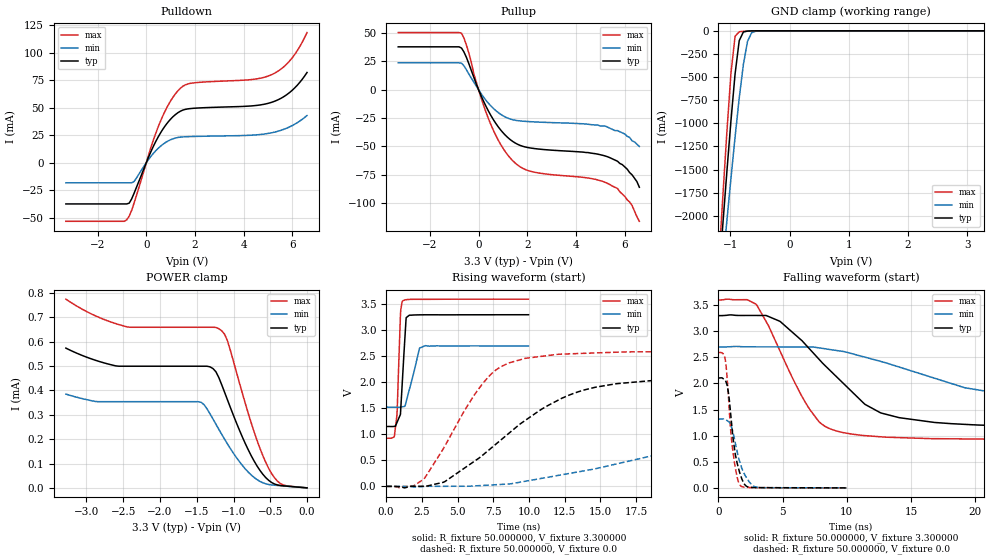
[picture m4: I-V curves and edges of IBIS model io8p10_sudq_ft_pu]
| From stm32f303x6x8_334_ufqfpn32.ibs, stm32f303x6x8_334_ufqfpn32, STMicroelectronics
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|   Model io8p10_sudq_ft_pu
[Model]  io8p10_sudq_ft_pu
Model_type I/O
Polarity   Non-Inverting
Enable   Active-Low
Vinl =   0.990000V
Vinh =   2.310000V
Vmeas =  1.650000V
Cref =   50.000000pF
Rref =   100.000000M
Vref =   0.0V
C_comp   1.970900pF   1.892300pF   2.063200pF
[Temperature Range]   25.000000   0.125000k   -40.000000
[Pullup Reference]   3.300000V   2.700000V   3.600000V
[Pulldown Reference]   0.0V   0.0V   0.0V
[POWER Clamp Reference]   3.300000V   2.700000V   3.600000V
[GND Clamp Reference]   0.0V   0.0V   0.0V
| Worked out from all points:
|   slope of the pulldown table from 0 to 0.495 V, typ, clamps not added: 20.9 ohm
|   slope of the pullup table from 0 to 0.495 V, typ, clamps not added: 22.2 ohm
|   GND clamp passes 1 mA (typ) near -0.64 V on its own axis
|   rising waveform, R_fixture 50.000000, V_fixture 3.300000: 20-80 % time 274ps typ, 646ps min, 201ps max; typ from 1.15 V to 3.3 V
|   rising waveform, R_fixture 50.000000, V_fixture 0.0: 20-80 % time 6.38ns typ, 15.3ns min, 3.53ns max; typ from 0.001 V to 2.1 V
|   falling waveform, R_fixture 50.000000, V_fixture 3.300000: 20-80 % time 5.28ns typ, 11.2ns min, 3.27ns max; typ from 3.3 V to 1.15 V
|   falling waveform, R_fixture 50.000000, V_fixture 0.0: 20-80 % time 666ps typ, 883ps min, 543ps max; typ from 2.1 V to 0.001 V
[Pulldown]
|Voltage   I(typ)   I(min)   I(max)
-3.3V     -37.45mA   -18.2mA    -53.24mA
-800mV    -37.45mA   -18.2mA    -51.9mA
-700mV    -36.7mA    -18.2mA    -48.48mA
-500mV    -27.71mA   -17.01mA   -36.65mA
500mV     23.91mA    13.38mA    33.24mA
900mV     37.17mA    19.88mA    52.48mA
1.3V      45.55mA    23.01mA    65.5mA
1.8V      49.29mA    23.83mA    72.18mA
4.4V      51.88mA    25.21mA    75.91mA
5.2V      55.41mA    27.53mA    80.72mA
5.9V      64.2mA     32.82mA    93.01mA
6.6V      82.13mA    42.97mA    118.5mA
[Pullup]
|Voltage   I(typ)   I(min)   I(max)
-3.3V     37.88mA    23.78mA    50.47mA
-700mV    36.78mA    23.49mA    49.96mA
-500mV    28.56mA    17.66mA    39.44mA
0V        90fA       16.1pA     0A
400mV     -18.61mA   -11.78mA   -25.23mA
900mV     -35.28mA   -21.55mA   -48mA
1.4V      -45.55mA   -26.41mA   -62.54mA
2.2V      -51.57mA   -28.22mA   -72.25mA
5.3V      -59.1mA    -33mA      -82.6mA
5.7V      -63mA      -36mA      -87mA
6.2V      -73mA      -42mA      -99mA
6.6V      -86mA      -50mA      -116mA
[GND_clamp]
|Voltage   I(typ)   I(min)   I(max)
-3.3V     -9.525A    -9.501A    -9.513A
-1.2V     -2.719A    -3.023A    -2.568A
-1.13V    -2.122A    -2.541A    -1.826A
-1.06V    -1.537A    -2.065A    -1.111A
-990mV    -975.7mA   -1.599A    -462mA
-920mV    -467.4mA   -1.149A    -59mA
-850mV    -106.6mA   -727.3mA   -10.11mA
-780mV    -13.06mA   -365.4mA   -5.254mA
-710mV    -3.045mA   -114.8mA   -2.635mA
-640mV    -943.2uA   -20.16mA   -905.7uA
-570mV    -199.4uA   -3.959mA   -156.8uA
3.28V     0A         0A         0A
[POWER_clamp]
|Voltage   I(typ)   I(min)   I(max)
-3.28V    574uA      385.1uA    775.2uA
-2.88V    524.3uA    354.9uA    706.9uA
-2.44V    499.6uA    353.9uA    660.7uA
-1.44V    499.6uA    351.4uA    659.6uA
-1.28V    490.1uA    283.2uA    659.6uA
-1.16V    423.2uA    219.6uA    645uA
-1.08V    359.8uA    179.3uA    602.1uA
-800mV    156.6uA    65uA       306.5uA
-640mV    71.59uA    26.48uA    162uA
-520mV    30.4uA     13.8uA     79.2uA
-360mV    9.635uA    8.674uA    17.24uA
0V        0A         0A         0A
[Ramp]
| variable   typ   min   max
dV/dt_r  1.26186/6.36665n   0.77938/15.29875n   1.55433/3.52236n
dV/dt_f  1.28856/5.27411n   0.69852/11.19498n   1.60393/3.26324n
R_load = 50.000000
[Rising Waveform]
R_fixture= 50.000000
V_fixture= 3.300000
V_fixture_min= 2.700000
V_fixture_max= 3.600000
|time   V(typ)   V(min)   V(max)
0s        1.152V     1.524V     926.8mV
560.6ps   1.154V     1.523V     949.5mV
760.8ps   1.231V     1.522V     1.384V
1.001ns   1.385V     1.525V     3.294V
1.141ns   2.053V     1.531V     3.56V
1.401ns   3.243V     1.629V     3.589V
1.622ns   3.291V     1.859V     3.594V
2.342ns   3.298V     2.66V      3.596V
2.743ns   3.299V     2.705V     3.596V
9.97ns    3.3V       2.7V       3.6V
[Rising Waveform]
R_fixture= 50.000000
V_fixture= 0.0
V_fixture_min= 0.0
V_fixture_max= 0.0
|time   V(typ)   V(min)   V(max)
0s        1.069mV    1.205mV    1.033mV
2.603ns   3.942mV    -2.244mV   135.1mV
4.104ns   91.8mV     2.857mV    773.7mV
6.907ns   634.6mV    21.21mV    2.025V
8.008ns   886.6mV    38.06mV    2.297V
9.71ns    1.263V     97.87mV    2.459V
13.61ns   1.833V     288mV      2.556V
19.02ns   2.044V     613.4mV    2.588V
32.33ns   2.101V     1.168V     2.593V
49.85ns   2.105V     1.317V     2.592V
[Falling Waveform]
R_fixture= 50.000000
V_fixture= 3.300000
V_fixture_min= 2.700000
V_fixture_max= 3.600000
|time   V(typ)   V(min)   V(max)
0s        3.3V       2.7V       3.6V
2.903ns   3.303V     2.701V     3.521V
4.805ns   3.187V     2.701V     2.615V
7.107ns   2.658V     2.697V     1.504V
8.008ns   2.416V     2.675V     1.229V
9.61ns    2.03V      2.617V     1.065V
12.61ns   1.439V     2.424V     979.1mV
16.82ns   1.254V     2.102V     943.3mV
24.52ns   1.176V     1.709V     928.7mV
49.85ns   1.152V     1.524V     926.8mV
[Falling Waveform]
R_fixture= 50.000000
V_fixture= 0.0
V_fixture_min= 0.0
V_fixture_max= 0.0
|time   V(typ)   V(min)   V(max)
0s        2.105V     1.317V     2.592V
520.5ps   2.063V     1.316V     2.47V
760.8ps   1.845V     1.274V     1.805V
961ps     1.386V     1.195V     1.072V
1.081ns   1.075V     1.116V     781.5mV
1.441ns   486.9mV    708mV      218.4mV
1.742ns   227.3mV    434.5mV    36.22mV
2.162ns   33.82mV    203.7mV    10.05mV
3.003ns   5.636mV    10.96mV    6.5mV
9.97ns    1.069mV    1.205mV    1.033mV
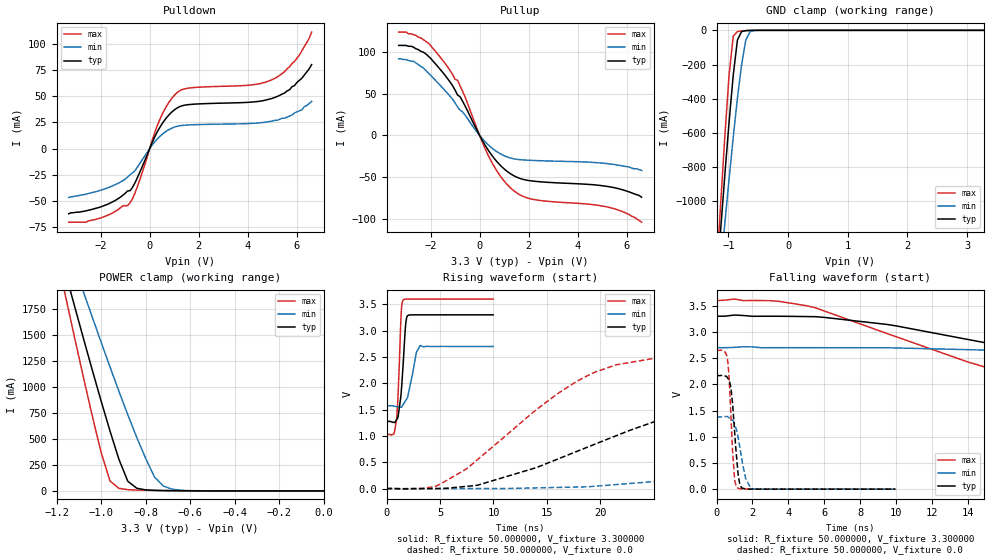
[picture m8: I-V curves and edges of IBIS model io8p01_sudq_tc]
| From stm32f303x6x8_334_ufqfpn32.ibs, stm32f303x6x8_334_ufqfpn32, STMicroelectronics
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|   Model io8p01_sudq_tc
[Model]  io8p01_sudq_tc
Model_type I/O
Polarity   Non-Inverting
Enable   Active-Low
Vinl =   0.990000V
Vinh =   2.310000V
Vmeas =  1.650000V
Cref =   50.000000pF
Rref =   100.000000M
Vref =   0.0V
C_comp   1.329900pF   1.255600pF   1.431200pF
[Temperature Range]   25.000000   0.125000k   -40.000000
[Pullup Reference]   3.300000V   2.700000V   3.600000V
[Pulldown Reference]   0.0V   0.0V   0.0V
[POWER Clamp Reference]   3.300000V   2.700000V   3.600000V
[GND Clamp Reference]   0.0V   0.0V   0.0V
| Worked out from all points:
|   slope of the pulldown table from 0 to 0.495 V, typ, clamps not added: 21.3 ohm
|   slope of the pullup table from 0 to 0.495 V, typ, clamps not added: 20.9 ohm
|   GND clamp passes 1 mA (typ) near -0.67 V on its own axis
|   POWER clamp passes 1 mA (typ) near -0.60 V on its own axis
|   rising waveform, R_fixture 50.000000, V_fixture 3.300000: 20-80 % time 415ps typ, 659ps min, 304ps max; typ from 1.27 V to 3.3 V
|   rising waveform, R_fixture 50.000000, V_fixture 0.0: 20-80 % time 18.4ns typ, 45.6ns min, 10.1ns max; typ from 0 V to 2.17 V
|   falling waveform, R_fixture 50.000000, V_fixture 3.300000: 20-80 % time 25.7ns typ, 44.2ns min, 16.4ns max; typ from 3.3 V to 1.27 V
|   falling waveform, R_fixture 50.000000, V_fixture 0.0: 20-80 % time 301ps typ, 443ps min, 235ps max; typ from 2.17 V to 0 V
[Pulldown]
|Voltage   I(typ)   I(min)   I(max)
-3.3V     -62mA      -46.4mA    -70mA
-2V       -55.5mA    -39.6mA    -66mA
-800mV    -40.04mA   -24.89mA   -51.58mA
-500mV    -27.57mA   -17.6mA    -36.07mA
400mV     19.71mA    11.36mA    27.01mA
700mV     29.83mA    16.93mA    40.97mA
1.1V      38.46mA    21.2mA     53.02mA
1.6V      41.98mA    22.62mA    57.7mA
4.1V      44.26mA    24mA       60.59mA
5V        47.9mA     26.3mA     65.8mA
5.9V      60mA       34mA       83mA
6.6V      80mA       45mA       111mA
[Pullup]
|Voltage   I(typ)   I(min)   I(max)
-3.3V     108mA      92mA       124mA
-2.7V     106mA      89mA       121mA
-2.2V     98mA       78.2mA     113mA
-1.4V     71.8mA     53.5mA     86.1mA
-900mV    48.51mA    34.23mA    66.14mA
-700mV    41.33mA    28.36mA    53.31mA
400mV     -19.77mA   -12.52mA   -26.8mA
900mV     -37.48mA   -22.89mA   -50.99mA
1.4V      -48.39mA   -28.06mA   -66.43mA
2.2V      -54.79mA   -29.98mA   -76.75mA
5.3V      -61.6mA    -34.2mA    -86.4mA
6.6V      -74mA      -42mA      -104mA
[GND_clamp]
|Voltage   I(typ)   I(min)   I(max)
-3.3V     -9.739A    -9.975A    -9.587A
-1.2V     -1.489A    -1.65A     -1.416A
-1.13V    -1.162A    -1.385A    -1.009A
-1.06V    -842.2mA   -1.125A    -616.9mA
-990mV    -537.1mA   -870.1mA   -263mA
-920mV    -262.4mA   -625.3mA   -33.96mA
-850mV    -56.94mA   -397.4mA   -7.08mA
-780mV    -7.011mA   -202.2mA   -3.71mA
-710mV    -1.778mA   -58.23mA   -1.736mA
-640mV    -550uA     -8.783mA   -542.4uA
-570mV    -109.8uA   -1.292mA   -86.89uA
3.28V     0A         0A         0A
[POWER_clamp]
|Voltage   I(typ)   I(min)   I(max)
-3.28V    9.897A     9.838A     9.594A
-1.16V    2.103A     2.419A     1.88A
-1.12V    1.788A     2.17A      1.488A
-1.08V    1.476A     1.923A     1.102A
-1V       868.1mA    1.435A     373.1mA
-960mV    578.2mA    1.196A     96.06mA
-880mV    93.24mA    734.1mA    12.01mA
-840mV    26.3mA     517.4mA    8.56mA
-760mV    5.106mA    134mA      5.119mA
-720mV    3.355mA    46.34mA    3.808mA
-600mV    1.005mA    2.564mA    1.072mA
0V        0A         0A         0A
[Ramp]
| variable   typ   min   max
dV/dt_r  1.30032/18.37567n   0.82686/45.50508n   1.58898/10.13318n
dV/dt_f  1.21512/25.71869n   0.67734/44.12424n   1.54260/16.40231n
R_load = 50.000000
[Rising Waveform]
R_fixture= 50.000000
V_fixture= 3.300000
V_fixture_min= 2.700000
V_fixture_max= 3.600000
|time   V(typ)   V(min)   V(max)
0s        1.275V     1.571V     1.029V
700.7ps   1.256V     1.567V     1.042V
940.9ps   1.309V     1.554V     1.306V
1.061ns   1.347V     1.549V     1.698V
1.381ns   1.855V     1.545V     3.367V
1.582ns   2.457V     1.604V     3.588V
1.902ns   3.262V     1.708V     3.599V
2.783ns   3.3V       2.578V     3.6V
3.143ns   3.3V       2.716V     3.6V
9.97ns    3.3V       2.7V       3.6V
[Rising Waveform]
R_fixture= 50.000000
V_fixture= 0.0
V_fixture_min= 0.0
V_fixture_max= 0.0
|time   V(typ)   V(min)   V(max)
0s        1.051nV    9.611nV    1.582nV
5.005ns   469.8uV    -186.9uV   81.71mV
8.509ns   63.64mV    54.44uV    550.2mV
15.52ns   520.2mV    19.22mV    1.729V
19.52ns   846.5mV    44.88mV    2.215V
25.53ns   1.304V     140.6mV    2.491V
33.53ns   1.763V     268.3mV    2.593V
47.55ns   2.063V     575.7mV    2.637V
88.59ns   2.166V     1.191V     2.649V
249.2ns   2.167V     1.378V     2.648V
[Falling Waveform]
R_fixture= 50.000000
V_fixture= 3.300000
V_fixture_min= 2.700000
V_fixture_max= 3.600000
|time   V(typ)   V(min)   V(max)
0s        3.3V       2.7V       3.6V
3.003ns   3.3V       2.7V       3.598V
5.506ns   3.292V     2.7V       3.462V
14.01ns   2.857V     2.662V     2.428V
21.52ns   2.389V     2.546V     1.754V
30.03ns   1.984V     2.38V      1.304V
40.04ns   1.664V     2.188V     1.114V
66.07ns   1.336V     1.83V      1.036V
105.6ns   1.278V     1.625V     1.028V
249.2ns   1.275V     1.571V     1.029V
[Falling Waveform]
R_fixture= 50.000000
V_fixture= 0.0
V_fixture_min= 0.0
V_fixture_max= 0.0
|time   V(typ)   V(min)   V(max)
0s        2.167V     1.378V     2.648V
620.6ps   2.121V     1.382V     2.449V
700.7ps   2.075V     1.363V     2.13V
820.8ps   1.878V     1.334V     1.257V
1.001ns   1.131V     1.241V     223mV
1.161ns   445.9mV    1.058V     25.76mV
1.381ns   33.8mV     632.9mV    3.628mV
1.622ns   5.857mV    204.8mV    542.5uV
1.942ns   613uV      4.191mV    128.7uV
9.97ns    1.051nV    9.611nV    1.582nV
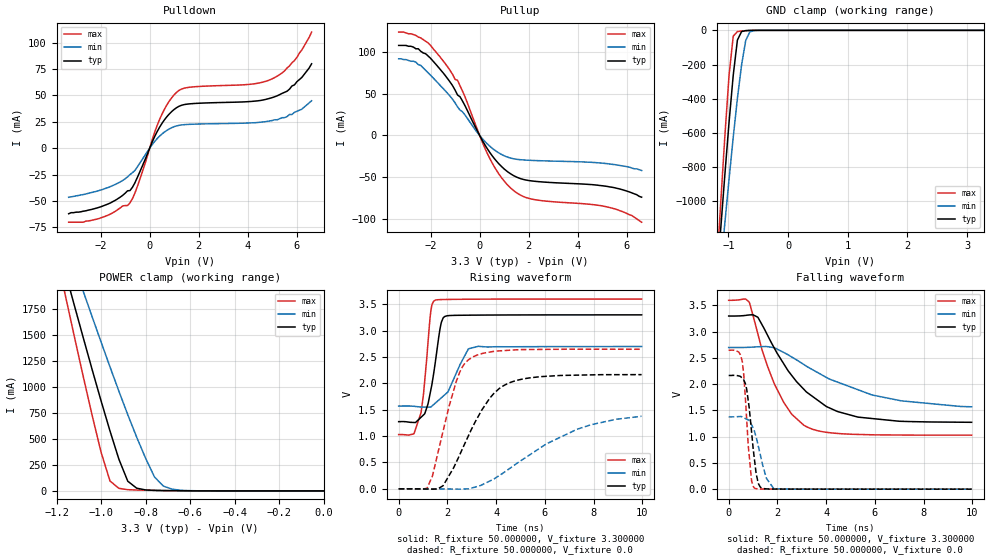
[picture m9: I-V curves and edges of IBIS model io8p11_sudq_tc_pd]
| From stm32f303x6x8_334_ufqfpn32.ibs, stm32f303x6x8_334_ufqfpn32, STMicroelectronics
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|   Model io8p11_sudq_tc_pd
[Model]  io8p11_sudq_tc_pd
Model_type I/O
Polarity   Non-Inverting
Enable   Active-Low
Vinl =   0.990000V
Vinh =   2.310000V
Vmeas =  1.650000V
Cref =   30.000000pF
Rref =   100.000000M
Vref =   0.0V
C_comp   1.329900pF   1.255600pF   1.431200pF
[Temperature Range]   25.000000   0.125000k   -40.000000
[Pullup Reference]   3.300000V   2.700000V   3.600000V
[Pulldown Reference]   0.0V   0.0V   0.0V
[POWER Clamp Reference]   3.300000V   2.700000V   3.600000V
[GND Clamp Reference]   0.0V   0.0V   0.0V
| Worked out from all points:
|   slope of the pulldown table from 0 to 0.495 V, typ, clamps not added: 21.3 ohm
|   slope of the pullup table from 0 to 0.495 V, typ, clamps not added: 20.9 ohm
|   GND clamp passes 1 mA (typ) near -0.66 V on its own axis
|   POWER clamp passes 1 mA (typ) near -0.60 V on its own axis
|   rising waveform, R_fixture 50.000000, V_fixture 3.300000: 20-80 % time 415ps typ, 734ps min, 311ps max; typ from 1.27 V to 3.3 V
|   rising waveform, R_fixture 50.000000, V_fixture 0.0: 20-80 % time 1.47ns typ, 2.98ns min, 896ps max; typ from 0 V to 2.17 V
|   falling waveform, R_fixture 50.000000, V_fixture 3.300000: 20-80 % time 2.06ns typ, 3.13ns min, 1.29ns max; typ from 3.3 V to 1.27 V
|   falling waveform, R_fixture 50.000000, V_fixture 0.0: 20-80 % time 303ps typ, 447ps min, 236ps max; typ from 2.17 V to 0 V
[Pulldown]
|Voltage   I(typ)   I(min)   I(max)
-3.3V     -62mA      -46.4mA    -70mA
-2.1V     -56.2mA    -40.3mA    -66.8mA
-800mV    -40.04mA   -24.9mA    -51.58mA
-500mV    -27.57mA   -17.6mA    -36.07mA
400mV     19.71mA    11.36mA    27.01mA
700mV     29.83mA    16.93mA    40.97mA
1.1V      38.46mA    21.2mA     53.02mA
1.6V      41.98mA    22.62mA    57.7mA
4.1V      44.26mA    24mA       60.59mA
5V        48mA       26.3mA     65.8mA
5.9V      60mA       34mA       83mA
6.6V      80mA       45mA       110mA
[Pullup]
|Voltage   I(typ)   I(min)   I(max)
-3.3V     108mA      92mA       124mA
-2.6V     104mA      88mA       120mA
-2.2V     98mA       78.2mA     113mA
-1.4V     71.8mA     53.6mA     86.1mA
-900mV    48.51mA    34.23mA    66.14mA
-700mV    41.33mA    28.36mA    53.31mA
400mV     -19.77mA   -12.52mA   -26.8mA
900mV     -37.48mA   -22.89mA   -50.99mA
1.4V      -48.39mA   -28.06mA   -66.43mA
2.2V      -54.79mA   -29.98mA   -76.75mA
5.3V      -61.7mA    -34.2mA    -86.4mA
6.6V      -74mA      -42mA      -104mA
[GND_clamp]
|Voltage   I(typ)   I(min)   I(max)
-3.3V     -9.739A    -9.975A    -9.587A
-1.2V     -1.489A    -1.65A     -1.416A
-1.13V    -1.162A    -1.385A    -1.009A
-1.06V    -842.3mA   -1.125A    -616.9mA
-990mV    -537.1mA   -870.2mA   -263mA
-920mV    -262.5mA   -625.3mA   -33.98mA
-850mV    -56.96mA   -397.5mA   -7.097mA
-780mV    -7.026mA   -202.3mA   -3.727mA
-710mV    -1.792mA   -58.24mA   -1.753mA
-640mV    -564.1uA   -8.795mA   -558.4uA
-570mV    -123.3uA   -1.303mA   -102.2uA
3.28V     84.11uA    64.12uA    93.81uA
[POWER_clamp]
|Voltage   I(typ)   I(min)   I(max)
-3.28V    9.897A     9.838A     9.594A
-1.16V    2.103A     2.419A     1.88A
-1.12V    1.788A     2.17A      1.488A
-1.08V    1.476A     1.923A     1.102A
-1V       868.1mA    1.435A     373.1mA
-960mV    578.2mA    1.196A     96.06mA
-880mV    93.24mA    734.1mA    12.01mA
-840mV    26.3mA     517.4mA    8.56mA
-760mV    5.106mA    134mA      5.119mA
-720mV    3.355mA    46.34mA    3.808mA
-600mV    1.005mA    2.564mA    1.072mA
0V        0A         0A         0A
[Ramp]
| variable   typ   min   max
dV/dt_r  1.29942/1.47394n   0.78822/2.97432n   1.58796/0.89539n
dV/dt_f  1.21386/2.06053n   0.65940/3.12926n   1.54218/1.29056n
R_load = 50.000000
[Rising Waveform]
R_fixture= 50.000000
V_fixture= 3.300000
V_fixture_min= 2.700000
V_fixture_max= 3.600000
|time   V(typ)   V(min)   V(max)
0s        1.274V     1.569V     1.029V
620.6ps   1.258V     1.565V     1.042V
920.9ps   1.358V     1.551V     1.45V
1.081ns   1.44V      1.551V     2.112V
1.321ns   1.879V     1.551V     3.376V
1.502ns   2.394V     1.625V     3.577V
1.702ns   3.046V     1.707V     3.588V
1.822ns   3.238V     1.756V     3.59V
2.863ns   3.293V     2.655V     3.596V
9.97ns    3.299V     2.699V     3.599V
[Rising Waveform]
R_fixture= 50.000000
V_fixture= 0.0
V_fixture_min= 0.0
V_fixture_max= 0.0
|time   V(typ)   V(min)   V(max)
0s        -62.44uV   -29.93uV   -44.66uV
1.161ns   -3.614mV   -95.46uV   9.224mV
1.401ns   -6.02mV    -580.1uV   271.6mV
1.822ns   59.24mV    -2.243mV   1.093V
2.362ns   503.9mV    -4.959mV   2.035V
3.003ns   1.143V     15.81mV    2.49V
3.884ns   1.798V     181.5mV    2.605V
4.725ns   2.04V      441.7mV    2.633V
7.327ns   2.156V     1.131V     2.648V
9.97ns    2.166V     1.377V     2.647V
[Falling Waveform]
R_fixture= 50.000000
V_fixture= 3.300000
V_fixture_min= 2.700000
V_fixture_max= 3.600000
|time   V(typ)   V(min)   V(max)
0s        3.299V     2.699V     3.599V
840.8ps   3.319V     2.703V     3.566V
1.201ns   3.274V     2.713V     2.953V
1.882ns   2.68V      2.694V     2V
2.583ns   2.17V      2.52V      1.431V
3.163ns   1.865V     2.352V     1.198V
4.024ns   1.571V     2.125V     1.082V
5.305ns   1.373V     1.895V     1.043V
7.087ns   1.293V     1.683V     1.031V
9.97ns    1.274V     1.569V     1.029V
[Falling Waveform]
R_fixture= 50.000000
V_fixture= 0.0
V_fixture_min= 0.0
V_fixture_max= 0.0
|time   V(typ)   V(min)   V(max)
0s        2.166V     1.377V     2.647V
400.4ps   2.159V     1.382V     2.615V
560.6ps   2.114V     1.375V     2.427V
740.7ps   1.901V     1.333V     1.319V
940.9ps   1.084V     1.224V     155.9mV
1.081ns   476.2mV    1.068V     15.33mV
1.301ns   37.65mV    650.6mV    3.063mV
1.542ns   6.098mV    218.4mV    1.826mV
1.862ns   2.175mV    5.314mV    1.32mV
9.97ns    -62.44uV   -29.93uV   -44.66uV
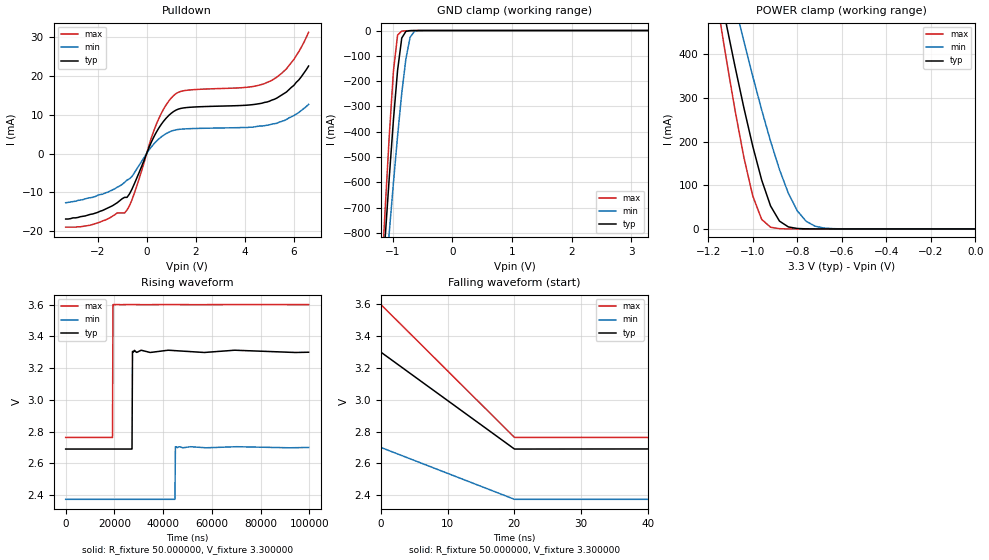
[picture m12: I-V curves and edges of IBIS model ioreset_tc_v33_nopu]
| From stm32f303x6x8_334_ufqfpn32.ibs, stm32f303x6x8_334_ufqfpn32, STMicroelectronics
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|   Model ioreset_tc_v33_nopu
[Model]  ioreset_tc_v33_nopu
Model_type I/O_open_drain
Polarity   Inverting
Enable   Active-High
Vinl =   0.990000V
Vinh =   2.310000V
Vmeas =  1.650000V
Cref =   1.0000000000000001E-7F
Rref =   1.000000k
Vref =   3.300000V
C_comp   0.983670pF   0.932330pF   1.052400pF
[Temperature Range]   25.000000   0.125000k   -40.000000
[Pullup Reference]   3.300000V   2.700000V   3.600000V
[Pulldown Reference]   0.0V   0.0V   0.0V
[POWER Clamp Reference]   3.300000V   2.700000V   3.600000V
[GND Clamp Reference]   0.0V   0.0V   0.0V
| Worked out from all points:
|   slope of the pulldown table from 0 to 0.495 V, typ, clamps not added: 75.3 ohm
|   GND clamp passes 1 mA (typ) near -0.72 V on its own axis
|   POWER clamp passes 1 mA (typ) near -0.80 V on its own axis
|   rising waveform, R_fixture 50.000000, V_fixture 3.300000: 20-80 % time 119ns typ, 119ns min, 120ns max; typ from 2.69 V to 3.3 V
|   falling waveform, R_fixture 50.000000, V_fixture 3.300000: 20-80 % time 12ns typ, 12ns min, 12ns max; typ from 3.3 V to 2.69 V
[Pulldown]
|Voltage   I(typ)   I(min)   I(max)
-3.3V     -16.9mA    -12.7mA    -19mA
-1.8V     -14.7mA    -10.5mA    -17.4mA
-800mV    -11.31mA   -6.86mA    -14.57mA
-500mV    -7.789mA   -4.969mA   -10.19mA
400mV     5.567mA    3.207mA    7.636mA
800mV     9.174mA    5.171mA    12.62mA
1.2V      11.24mA    6.137mA    15.5mA
4.2V      12.55mA    6.8mA      17.2mA
5V        13.5mA     7.4mA      18.6mA
5.7V      15.9mA     8.8mA      21.9mA
6.2V      19mA       10.6mA     26.3mA
6.6V      22.6mA     12.7mA     31.3mA
[GND_clamp]
|Voltage   I(typ)   I(min)   I(max)
-3.3V     -9.104A    -7.777A    -9.724A
-1.2V     -1.076A    -1.208A    -1.024A
-1.13V    -825.8mA   -1.002A    -713.7mA
-1.06V    -583.4mA   -799.8mA   -418.8mA
-990mV    -355.1mA   -603.5mA   -161.7mA
-920mV    -157.4mA   -417mA     -18.13mA
-850mV    -29.69mA   -247.7mA   -2.329mA
-780mV    -3.137mA   -111.1mA   -1.063mA
-710mV    -585.1uA   -26.85mA   -494.2uA
-640mV    -162uA     -4.074mA   -154.9uA
-500mV    -3.792uA   -82.2uA    -1.945uA
3.28V     0A         0A         0A
[POWER_clamp]
|Voltage   I(typ)   I(min)   I(max)
-3.28V    6.625A     5.702A     8.109A
-1.16V    574.4mA    684.1mA    518.4mA
-1.12V    471.9mA    597.6mA    392.3mA
-1.08V    372.4mA    512.6mA    272.6mA
-1.04V    277.4mA    429.7mA    163.9mA
-1V       189.2mA    349.3mA    75.44mA
-960mV    111.9mA    272.5mA    21.88mA
-880mV    17.91mA    135.9mA    598.3uA
-800mV    1.058mA    41.4mA     18.57uA
-760mV    236.1uA    17.42mA    7.299uA
-640mV    5.231uA    683.9uA    3.044uA
0V        0A         0A         0A
[Ramp]
| variable   typ   min   max
dV/dt_r  0.37020/60.41123n   0.19806/60.73597n   0.50196/60.00000n
dV/dt_f  0.36636/60.12802n   0.19602/60.00000n   0.50256/60.01433n
R_load = 50.000000
[Rising Waveform]
R_fixture= 50.000000
V_fixture= 3.300000
V_fixture_min= 2.700000
V_fixture_max= 3.600000
|time   V(typ)   V(min)   V(max)
0s        2.69V      2.373V     2.763V
19.22us   2.69V      2.373V     2.763V
19.42us   2.69V      2.373V     3.6V
27.23us   2.69V      2.373V     3.6V
27.43us   3.305V     2.373V     3.6V
28.23us   3.312V     2.373V     3.6V
34.63us   3.299V     2.373V     3.6V
44.84us   3.31V      2.373V     3.6V
45.05us   3.31V      2.704V     3.6V
99.7us    3.3V       2.7V       3.6V
[Falling Waveform]
R_fixture= 50.000000
V_fixture= 3.300000
V_fixture_min= 2.700000
V_fixture_max= 3.600000
|time   V(typ)   V(min)   V(max)
0s        3.3V       2.7V       3.6V
20.02ns   2.69V      2.373V     2.763V
380.4ns   2.691V     2.373V     2.763V
9.97us    2.69V      2.373V     2.763V
